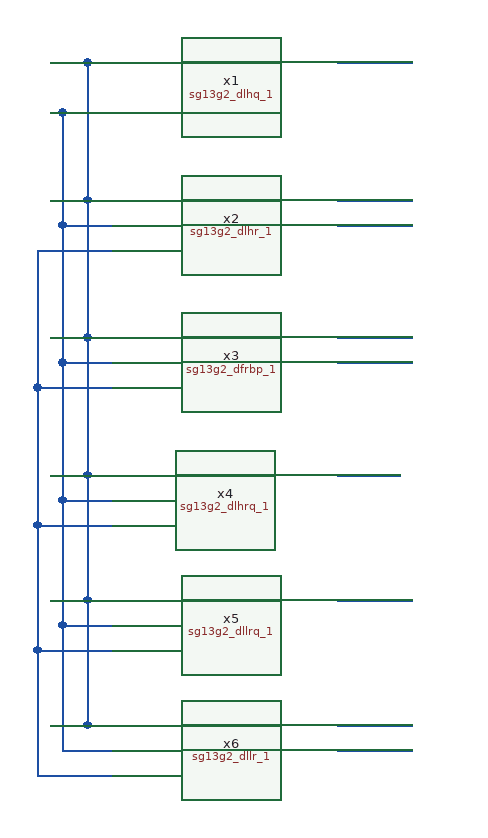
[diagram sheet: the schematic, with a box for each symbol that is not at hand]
v {xschem version=3.4.4 file_version=1.2
}
G {}
K {}
V {}
S {}
E {}
N -110 -20 -90 -20 {
lab=#net1}
N -130 20 -90 20 {
lab=#net2}
N 90 -20 150 -20 {
lab=#net3}
N -110 90 -90 90 {
lab=#net1}
N 90 90 150 90 {
lab=#net4}
N -110 -20 -110 90 {
lab=#net1}
N -140 -20 -110 -20 {
lab=#net1}
N -140 90 -110 90 {
lab=#net1}
N -140 20 -130 20 {
lab=#net2}
N -130 110 -90 110 {
lab=#net2}
N -130 20 -130 110 {
lab=#net2}
N 90 110 150 110 {
lab=#net5}
N -110 200 -90 200 {
lab=#net1}
N -110 90 -110 200 {
lab=#net1}
N -140 200 -110 200 {
lab=#net1}
N -130 110 -130 220 {
lab=#net2}
N -130 220 -90 220 {
lab=#net2}
N -150 240 -90 240 {
lab=#net6}
N -150 130 -150 240 {
lab=#net6}
N -150 130 -90 130 {
lab=#net6}
N 90 200 150 200 {
lab=#net7}
N 90 220 150 220 {
lab=#net8}
N -110 310 -90 310 {
lab=#net1}
N -130 330 -90 330 {
lab=#net2}
N -150 350 -90 350 {
lab=#net6}
N -150 240 -150 350 {
lab=#net6}
N -140 310 -110 310 {
lab=#net1}
N 90 310 140 310 {
lab=#net9}
N -110 410 -90 410 {
lab=#net1}
N -110 310 -110 410 {
lab=#net1}
N -110 200 -110 310 {
lab=#net1}
N -130 430 -90 430 {
lab=#net2}
N -130 330 -130 430 {
lab=#net2}
N -130 220 -130 330 {
lab=#net2}
N -150 450 -90 450 {
lab=#net6}
N -150 350 -150 450 {
lab=#net6}
N -140 410 -110 410 {
lab=#net1}
N 90 410 150 410 {
lab=#net10}
N -110 510 -90 510 {
lab=#net1}
N -110 410 -110 510 {
lab=#net1}
N -140 510 -110 510 {
lab=#net1}
N -130 530 -90 530 {
lab=#net2}
N -130 430 -130 530 {
lab=#net2}
N -150 550 -90 550 {
lab=#net6}
N -150 450 -150 550 {
lab=#net6}
N 90 510 150 510 {
lab=#net11}
N 90 530 150 530 {
lab=#net12}
C {sg13g2_stdcells/sg13g2_dlhq_1.sym} 0 0 0 0 {name=x1 VGND=VGND VNB=VNB VPB=VPB VPWR=VPWR prefix=sg13g2_ }
C {sg13g2_stdcells/sg13g2_dlhr_1.sym} 0 110 0 0 {name=x2 VGND=VGND VNB=VNB VPB=VPB VPWR=VPWR prefix=sg13g2_ }
C {sg13g2_stdcells/sg13g2_dfrbp_1.sym} 0 220 0 0 {name=x3 VGND=VGND VNB=VNB VPB=VPB VPWR=VPWR prefix=sg13g2_ }
C {sg13g2_stdcells/sg13g2_dlhrq_1.sym} 0 330 0 0 {name=x4 VGND=VGND VNB=VNB VPB=VPB VPWR=VPWR prefix=sg13g2_ }
C {sg13g2_stdcells/sg13g2_dllrq_1.sym} 0 430 0 0 {name=x5 VGND=VGND VNB=VNB VPB=VPB VPWR=VPWR prefix=sg13g2_ }
C {sg13g2_stdcells/sg13g2_dllr_1.sym} 0 530 0 0 {name=x6 VGND=VGND VNB=VNB VPB=VPB VPWR=VPWR prefix=sg13g2_ }
